VERSION 5.4 ;
NAMESCASESENSITIVE ON ;
BUSBITCHARS "[]" ;
DIVIDERCHAR "/" ;
UNITS
  DATABASE MICRONS 2000 ;
END UNITS
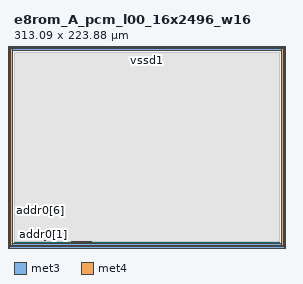
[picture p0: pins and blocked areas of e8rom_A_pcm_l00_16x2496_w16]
MACRO e8rom_A_pcm_l00_16x2496_w16
   CLASS BLOCK ;
   SIZE 313.09 BY 223.88 ;
   SYMMETRY X Y R90 ;
   PIN clk0
      DIRECTION INPUT ;
      PORT
         LAYER met3 ;
         RECT  0.53 9.705 1.02 10.195 ;
      END
   END clk0
   PIN cs0
      DIRECTION INPUT ;
      PORT
         LAYER met3 ;
         RECT  19.91 2.5 20.4 2.99 ;
      END
   END cs0
   PIN addr0[0]
      DIRECTION INPUT ;
      PORT
         LAYER met3 ;
         RECT  32.175 1.39 32.665 1.88 ;
      END
   END addr0[0]
   PIN addr0[1]
      DIRECTION INPUT ;
      PORT
         LAYER met3 ;
         RECT  34.215 1.39 34.705 1.88 ;
      END
   END addr0[1]
   PIN addr0[2]
      DIRECTION INPUT ;
      PORT
         LAYER met3 ;
         RECT  36.255 1.39 36.745 1.88 ;
      END
   END addr0[2]
   PIN addr0[3]
      DIRECTION INPUT ;
      PORT
         LAYER met3 ;
         RECT  38.295 1.39 38.785 1.88 ;
      END
   END addr0[3]
   PIN addr0[4]
      DIRECTION INPUT ;
      PORT
         LAYER met3 ;
         RECT  1.525 36.895 2.015 37.385 ;
      END
   END addr0[4]
   PIN addr0[5]
      DIRECTION INPUT ;
      PORT
         LAYER met3 ;
         RECT  3.565 36.895 4.055 37.385 ;
      END
   END addr0[5]
   PIN addr0[6]
      DIRECTION INPUT ;
      PORT
         LAYER met3 ;
         RECT  5.605 36.895 6.095 37.385 ;
      END
   END addr0[6]
   PIN addr0[7]
      DIRECTION INPUT ;
      PORT
         LAYER met3 ;
         RECT  7.645 36.895 8.135 37.385 ;
      END
   END addr0[7]
   PIN addr0[8]
      DIRECTION INPUT ;
      PORT
         LAYER met3 ;
         RECT  9.685 36.895 10.175 37.385 ;
      END
   END addr0[8]
   PIN addr0[9]
      DIRECTION INPUT ;
      PORT
         LAYER met3 ;
         RECT  11.725 36.895 12.215 37.385 ;
      END
   END addr0[9]
   PIN addr0[10]
      DIRECTION INPUT ;
      PORT
         LAYER met3 ;
         RECT  13.765 36.895 14.255 37.385 ;
      END
   END addr0[10]
   PIN addr0[11]
      DIRECTION INPUT ;
      PORT
         LAYER met3 ;
         RECT  15.805 36.895 16.295 37.385 ;
      END
   END addr0[11]
   PIN dout0[0]
      DIRECTION OUTPUT ;
      PORT
         LAYER met3 ;
         RECT  67.18 -0.16 67.67 0.33 ;
      END
   END dout0[0]
   PIN dout0[1]
      DIRECTION OUTPUT ;
      PORT
         LAYER met3 ;
         RECT  68.72 -0.16 69.21 0.33 ;
      END
   END dout0[1]
   PIN dout0[2]
      DIRECTION OUTPUT ;
      PORT
         LAYER met3 ;
         RECT  70.26 -0.16 70.75 0.33 ;
      END
   END dout0[2]
   PIN dout0[3]
      DIRECTION OUTPUT ;
      PORT
         LAYER met3 ;
         RECT  71.8 -0.16 72.29 0.33 ;
      END
   END dout0[3]
   PIN dout0[4]
      DIRECTION OUTPUT ;
      PORT
         LAYER met3 ;
         RECT  73.34 -0.16 73.83 0.33 ;
      END
   END dout0[4]
   PIN dout0[5]
      DIRECTION OUTPUT ;
      PORT
         LAYER met3 ;
         RECT  74.88 -0.16 75.37 0.33 ;
      END
   END dout0[5]
   PIN dout0[6]
      DIRECTION OUTPUT ;
      PORT
         LAYER met3 ;
         RECT  76.42 -0.16 76.91 0.33 ;
      END
   END dout0[6]
   PIN dout0[7]
      DIRECTION OUTPUT ;
      PORT
         LAYER met3 ;
         RECT  77.96 -0.16 78.45 0.33 ;
      END
   END dout0[7]
   PIN dout0[8]
      DIRECTION OUTPUT ;
      PORT
         LAYER met3 ;
         RECT  79.5 -0.16 79.99 0.33 ;
      END
   END dout0[8]
   PIN dout0[9]
      DIRECTION OUTPUT ;
      PORT
         LAYER met3 ;
         RECT  81.04 -0.16 81.53 0.33 ;
      END
   END dout0[9]
   PIN dout0[10]
      DIRECTION OUTPUT ;
      PORT
         LAYER met3 ;
         RECT  82.58 -0.16 83.07 0.33 ;
      END
   END dout0[10]
   PIN dout0[11]
      DIRECTION OUTPUT ;
      PORT
         LAYER met3 ;
         RECT  84.12 -0.16 84.61 0.33 ;
      END
   END dout0[11]
   PIN dout0[12]
      DIRECTION OUTPUT ;
      PORT
         LAYER met3 ;
         RECT  85.66 -0.16 86.15 0.33 ;
      END
   END dout0[12]
   PIN dout0[13]
      DIRECTION OUTPUT ;
      PORT
         LAYER met3 ;
         RECT  87.2 -0.16 87.69 0.33 ;
      END
   END dout0[13]
   PIN dout0[14]
      DIRECTION OUTPUT ;
      PORT
         LAYER met3 ;
         RECT  88.74 -0.16 89.23 0.33 ;
      END
   END dout0[14]
   PIN dout0[15]
      DIRECTION OUTPUT ;
      PORT
         LAYER met3 ;
         RECT  90.28 -0.16 90.77 0.33 ;
      END
   END dout0[15]
   PIN vccd1
      DIRECTION INOUT ;
      USE POWER ; 
      SHAPE ABUTMENT ; 
      PORT
         LAYER met4 ;
         RECT  -7.48 -7.48 -5.74 231.36 ;
         LAYER met4 ;
         RECT  318.83 -7.48 320.57 231.36 ;
         LAYER met3 ;
         RECT  -7.48 -7.48 320.57 -5.74 ;
         LAYER met3 ;
         RECT  -7.48 229.62 320.57 231.36 ;
      END
   END vccd1
   PIN vssd1
      DIRECTION INOUT ;
      USE GROUND ; 
      SHAPE ABUTMENT ; 
      PORT
         LAYER met4 ;
         RECT  315.35 -4.0 317.09 227.88 ;
         LAYER met3 ;
         RECT  -4.0 -4.0 317.09 -2.26 ;
         LAYER met4 ;
         RECT  -4.0 -4.0 -2.26 227.88 ;
         LAYER met3 ;
         RECT  -4.0 226.14 317.09 227.88 ;
      END
   END vssd1
   OBS
   LAYER  met1 ;
      RECT  0.62 0.62 312.47 223.26 ;
   LAYER  met2 ;
      RECT  0.62 0.62 312.47 223.26 ;
   LAYER  met3 ;
      RECT  0.62 0.62 1.62 9.105 ;
      RECT  1.62 9.105 312.47 10.795 ;
      RECT  1.62 0.62 19.31 1.9 ;
      RECT  1.62 1.9 19.31 3.59 ;
      RECT  1.62 3.59 19.31 9.105 ;
      RECT  19.31 0.62 21.0 1.9 ;
      RECT  19.31 3.59 21.0 9.105 ;
      RECT  21.0 3.59 312.47 9.105 ;
      RECT  21.0 0.62 31.575 0.79 ;
      RECT  21.0 0.79 31.575 1.9 ;
      RECT  31.575 0.62 33.265 0.79 ;
      RECT  21.0 1.9 31.575 2.48 ;
      RECT  21.0 2.48 31.575 3.59 ;
      RECT  31.575 2.48 33.265 3.59 ;
      RECT  33.265 2.48 312.47 3.59 ;
      RECT  33.265 0.79 33.615 1.9 ;
      RECT  33.265 1.9 33.615 2.48 ;
      RECT  35.305 0.79 35.655 1.9 ;
      RECT  35.305 1.9 35.655 2.48 ;
      RECT  37.345 0.79 37.695 1.9 ;
      RECT  37.345 1.9 37.695 2.48 ;
      RECT  39.385 1.9 312.47 2.48 ;
      RECT  0.62 10.795 0.925 36.295 ;
      RECT  0.62 36.295 0.925 37.985 ;
      RECT  0.62 37.985 0.925 223.26 ;
      RECT  0.925 10.795 1.62 36.295 ;
      RECT  0.925 37.985 1.62 223.26 ;
      RECT  1.62 10.795 2.615 36.295 ;
      RECT  1.62 37.985 2.615 223.26 ;
      RECT  2.615 10.795 312.47 36.295 ;
      RECT  2.615 37.985 312.47 223.26 ;
      RECT  2.615 36.295 2.965 37.985 ;
      RECT  4.655 36.295 5.005 37.985 ;
      RECT  6.695 36.295 7.045 37.985 ;
      RECT  8.735 36.295 9.085 37.985 ;
      RECT  10.775 36.295 11.125 37.985 ;
      RECT  12.815 36.295 13.165 37.985 ;
      RECT  14.855 36.295 15.205 37.985 ;
      RECT  16.895 36.295 312.47 37.985 ;
      RECT  33.265 0.62 66.58 0.79 ;
      RECT  39.385 0.79 66.58 0.93 ;
      RECT  39.385 0.93 66.58 1.9 ;
      RECT  66.58 0.93 68.27 1.9 ;
      RECT  68.27 0.93 312.47 1.9 ;
      RECT  91.37 0.62 312.47 0.79 ;
      RECT  91.37 0.79 312.47 0.93 ;
   LAYER  met4 ;
      RECT  0.62 0.62 312.47 223.26 ;
   END
END    e8rom_A_pcm_l00_16x2496_w16
END    LIBRARY
